VERSION 5.7 ;
BUSBITCHARS "[]" ;
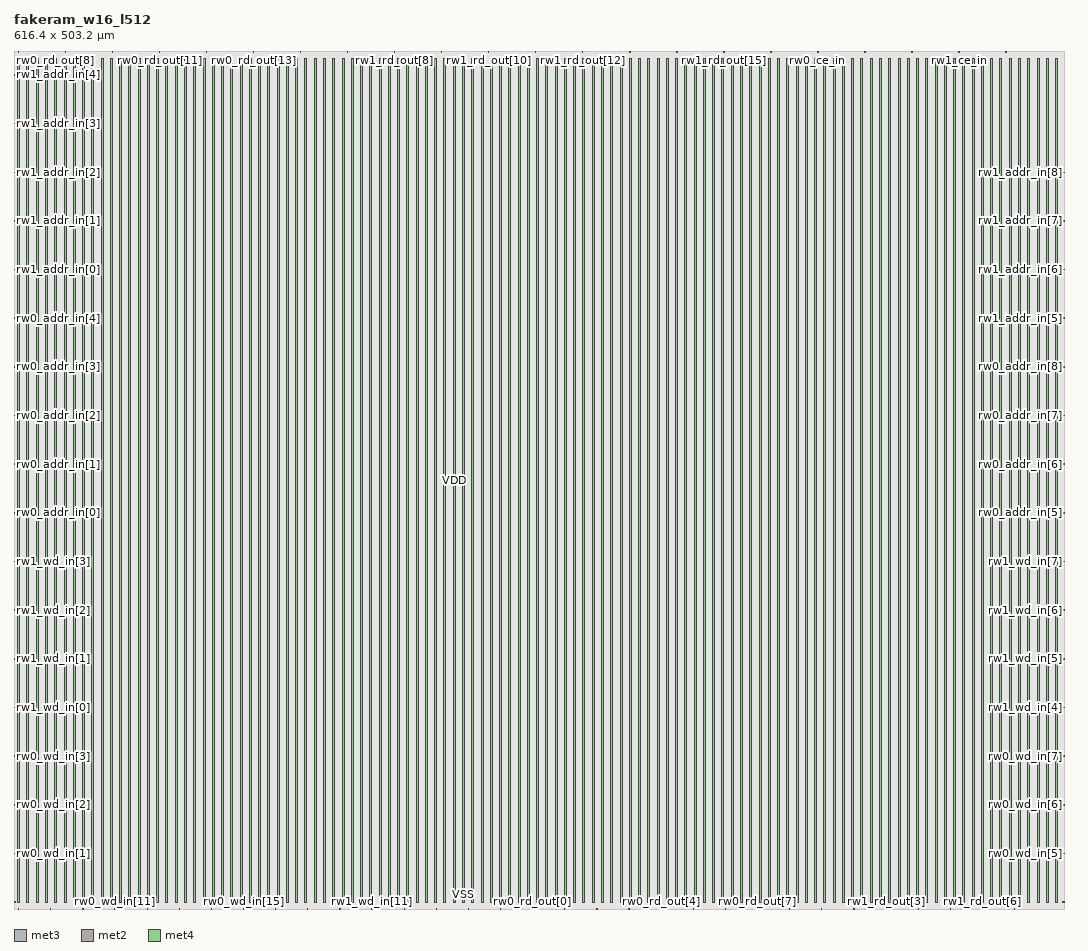
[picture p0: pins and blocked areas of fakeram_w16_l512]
MACRO fakeram_w16_l512
  FOREIGN fakeram_w16_l512 0 0 ;
  SYMMETRY X Y R90 ;
  SIZE 616.400 BY 503.200 ;
  CLASS BLOCK ;
  PIN rw0_wd_in[0]
    DIRECTION INPUT ;
    USE SIGNAL ;
    SHAPE ABUTMENT ;
    PORT
      LAYER met3 ;
      RECT 0.000 3.930 0.900 4.230 ;
    END
  END rw0_wd_in[0]
  PIN rw0_wd_in[1]
    DIRECTION INPUT ;
    USE SIGNAL ;
    SHAPE ABUTMENT ;
    PORT
      LAYER met3 ;
      RECT 0.000 32.490 0.900 32.790 ;
    END
  END rw0_wd_in[1]
  PIN rw0_wd_in[2]
    DIRECTION INPUT ;
    USE SIGNAL ;
    SHAPE ABUTMENT ;
    PORT
      LAYER met3 ;
      RECT 0.000 61.050 0.900 61.350 ;
    END
  END rw0_wd_in[2]
  PIN rw0_wd_in[3]
    DIRECTION INPUT ;
    USE SIGNAL ;
    SHAPE ABUTMENT ;
    PORT
      LAYER met3 ;
      RECT 0.000 89.610 0.900 89.910 ;
    END
  END rw0_wd_in[3]
  PIN rw0_wd_in[4]
    DIRECTION INPUT ;
    USE SIGNAL ;
    SHAPE ABUTMENT ;
    PORT
      LAYER met3 ;
      RECT 615.500 3.930 616.400 4.230 ;
    END
  END rw0_wd_in[4]
  PIN rw0_wd_in[5]
    DIRECTION INPUT ;
    USE SIGNAL ;
    SHAPE ABUTMENT ;
    PORT
      LAYER met3 ;
      RECT 615.500 32.490 616.400 32.790 ;
    END
  END rw0_wd_in[5]
  PIN rw0_wd_in[6]
    DIRECTION INPUT ;
    USE SIGNAL ;
    SHAPE ABUTMENT ;
    PORT
      LAYER met3 ;
      RECT 615.500 61.050 616.400 61.350 ;
    END
  END rw0_wd_in[6]
  PIN rw0_wd_in[7]
    DIRECTION INPUT ;
    USE SIGNAL ;
    SHAPE ABUTMENT ;
    PORT
      LAYER met3 ;
      RECT 615.500 89.610 616.400 89.910 ;
    END
  END rw0_wd_in[7]
  PIN rw0_wd_in[8]
    DIRECTION INPUT ;
    USE SIGNAL ;
    SHAPE ABUTMENT ;
    PORT
      LAYER met2 ;
      RECT 2.690 0.000 2.830 0.420 ;
    END
  END rw0_wd_in[8]
  PIN rw0_wd_in[9]
    DIRECTION INPUT ;
    USE SIGNAL ;
    SHAPE ABUTMENT ;
    PORT
      LAYER met2 ;
      RECT 21.550 0.000 21.690 0.420 ;
    END
  END rw0_wd_in[9]
  PIN rw0_wd_in[10]
    DIRECTION INPUT ;
    USE SIGNAL ;
    SHAPE ABUTMENT ;
    PORT
      LAYER met2 ;
      RECT 40.410 0.000 40.550 0.420 ;
    END
  END rw0_wd_in[10]
  PIN rw0_wd_in[11]
    DIRECTION INPUT ;
    USE SIGNAL ;
    SHAPE ABUTMENT ;
    PORT
      LAYER met2 ;
      RECT 59.270 0.000 59.410 0.420 ;
    END
  END rw0_wd_in[11]
  PIN rw0_wd_in[12]
    DIRECTION INPUT ;
    USE SIGNAL ;
    SHAPE ABUTMENT ;
    PORT
      LAYER met2 ;
      RECT 78.130 0.000 78.270 0.420 ;
    END
  END rw0_wd_in[12]
  PIN rw0_wd_in[13]
    DIRECTION INPUT ;
    USE SIGNAL ;
    SHAPE ABUTMENT ;
    PORT
      LAYER met2 ;
      RECT 96.990 0.000 97.130 0.420 ;
    END
  END rw0_wd_in[13]
  PIN rw0_wd_in[14]
    DIRECTION INPUT ;
    USE SIGNAL ;
    SHAPE ABUTMENT ;
    PORT
      LAYER met2 ;
      RECT 115.850 0.000 115.990 0.420 ;
    END
  END rw0_wd_in[14]
  PIN rw0_wd_in[15]
    DIRECTION INPUT ;
    USE SIGNAL ;
    SHAPE ABUTMENT ;
    PORT
      LAYER met2 ;
      RECT 134.710 0.000 134.850 0.420 ;
    END
  END rw0_wd_in[15]
  PIN rw1_wd_in[0]
    DIRECTION INPUT ;
    USE SIGNAL ;
    SHAPE ABUTMENT ;
    PORT
      LAYER met3 ;
      RECT 0.000 118.170 0.900 118.470 ;
    END
  END rw1_wd_in[0]
  PIN rw1_wd_in[1]
    DIRECTION INPUT ;
    USE SIGNAL ;
    SHAPE ABUTMENT ;
    PORT
      LAYER met3 ;
      RECT 0.000 146.730 0.900 147.030 ;
    END
  END rw1_wd_in[1]
  PIN rw1_wd_in[2]
    DIRECTION INPUT ;
    USE SIGNAL ;
    SHAPE ABUTMENT ;
    PORT
      LAYER met3 ;
      RECT 0.000 175.290 0.900 175.590 ;
    END
  END rw1_wd_in[2]
  PIN rw1_wd_in[3]
    DIRECTION INPUT ;
    USE SIGNAL ;
    SHAPE ABUTMENT ;
    PORT
      LAYER met3 ;
      RECT 0.000 203.850 0.900 204.150 ;
    END
  END rw1_wd_in[3]
  PIN rw1_wd_in[4]
    DIRECTION INPUT ;
    USE SIGNAL ;
    SHAPE ABUTMENT ;
    PORT
      LAYER met3 ;
      RECT 615.500 118.170 616.400 118.470 ;
    END
  END rw1_wd_in[4]
  PIN rw1_wd_in[5]
    DIRECTION INPUT ;
    USE SIGNAL ;
    SHAPE ABUTMENT ;
    PORT
      LAYER met3 ;
      RECT 615.500 146.730 616.400 147.030 ;
    END
  END rw1_wd_in[5]
  PIN rw1_wd_in[6]
    DIRECTION INPUT ;
    USE SIGNAL ;
    SHAPE ABUTMENT ;
    PORT
      LAYER met3 ;
      RECT 615.500 175.290 616.400 175.590 ;
    END
  END rw1_wd_in[6]
  PIN rw1_wd_in[7]
    DIRECTION INPUT ;
    USE SIGNAL ;
    SHAPE ABUTMENT ;
    PORT
      LAYER met3 ;
      RECT 615.500 203.850 616.400 204.150 ;
    END
  END rw1_wd_in[7]
  PIN rw1_wd_in[8]
    DIRECTION INPUT ;
    USE SIGNAL ;
    SHAPE ABUTMENT ;
    PORT
      LAYER met2 ;
      RECT 153.570 0.000 153.710 0.420 ;
    END
  END rw1_wd_in[8]
  PIN rw1_wd_in[9]
    DIRECTION INPUT ;
    USE SIGNAL ;
    SHAPE ABUTMENT ;
    PORT
      LAYER met2 ;
      RECT 172.430 0.000 172.570 0.420 ;
    END
  END rw1_wd_in[9]
  PIN rw1_wd_in[10]
    DIRECTION INPUT ;
    USE SIGNAL ;
    SHAPE ABUTMENT ;
    PORT
      LAYER met2 ;
      RECT 191.290 0.000 191.430 0.420 ;
    END
  END rw1_wd_in[10]
  PIN rw1_wd_in[11]
    DIRECTION INPUT ;
    USE SIGNAL ;
    SHAPE ABUTMENT ;
    PORT
      LAYER met2 ;
      RECT 210.150 0.000 210.290 0.420 ;
    END
  END rw1_wd_in[11]
  PIN rw1_wd_in[12]
    DIRECTION INPUT ;
    USE SIGNAL ;
    SHAPE ABUTMENT ;
    PORT
      LAYER met2 ;
      RECT 229.010 0.000 229.150 0.420 ;
    END
  END rw1_wd_in[12]
  PIN rw1_wd_in[13]
    DIRECTION INPUT ;
    USE SIGNAL ;
    SHAPE ABUTMENT ;
    PORT
      LAYER met2 ;
      RECT 247.870 0.000 248.010 0.420 ;
    END
  END rw1_wd_in[13]
  PIN rw1_wd_in[14]
    DIRECTION INPUT ;
    USE SIGNAL ;
    SHAPE ABUTMENT ;
    PORT
      LAYER met2 ;
      RECT 266.730 0.000 266.870 0.420 ;
    END
  END rw1_wd_in[14]
  PIN rw1_wd_in[15]
    DIRECTION INPUT ;
    USE SIGNAL ;
    SHAPE ABUTMENT ;
    PORT
      LAYER met2 ;
      RECT 285.590 0.000 285.730 0.420 ;
    END
  END rw1_wd_in[15]
  PIN rw0_rd_out[0]
    DIRECTION OUTPUT ;
    USE SIGNAL ;
    SHAPE ABUTMENT ;
    PORT
      LAYER met2 ;
      RECT 304.450 0.000 304.590 0.420 ;
    END
  END rw0_rd_out[0]
  PIN rw0_rd_out[1]
    DIRECTION OUTPUT ;
    USE SIGNAL ;
    SHAPE ABUTMENT ;
    PORT
      LAYER met2 ;
      RECT 323.310 0.000 323.450 0.420 ;
    END
  END rw0_rd_out[1]
  PIN rw0_rd_out[2]
    DIRECTION OUTPUT ;
    USE SIGNAL ;
    SHAPE ABUTMENT ;
    PORT
      LAYER met2 ;
      RECT 342.170 0.000 342.310 0.420 ;
    END
  END rw0_rd_out[2]
  PIN rw0_rd_out[3]
    DIRECTION OUTPUT ;
    USE SIGNAL ;
    SHAPE ABUTMENT ;
    PORT
      LAYER met2 ;
      RECT 361.030 0.000 361.170 0.420 ;
    END
  END rw0_rd_out[3]
  PIN rw0_rd_out[4]
    DIRECTION OUTPUT ;
    USE SIGNAL ;
    SHAPE ABUTMENT ;
    PORT
      LAYER met2 ;
      RECT 379.890 0.000 380.030 0.420 ;
    END
  END rw0_rd_out[4]
  PIN rw0_rd_out[5]
    DIRECTION OUTPUT ;
    USE SIGNAL ;
    SHAPE ABUTMENT ;
    PORT
      LAYER met2 ;
      RECT 398.750 0.000 398.890 0.420 ;
    END
  END rw0_rd_out[5]
  PIN rw0_rd_out[6]
    DIRECTION OUTPUT ;
    USE SIGNAL ;
    SHAPE ABUTMENT ;
    PORT
      LAYER met2 ;
      RECT 417.610 0.000 417.750 0.420 ;
    END
  END rw0_rd_out[6]
  PIN rw0_rd_out[7]
    DIRECTION OUTPUT ;
    USE SIGNAL ;
    SHAPE ABUTMENT ;
    PORT
      LAYER met2 ;
      RECT 436.470 0.000 436.610 0.420 ;
    END
  END rw0_rd_out[7]
  PIN rw0_rd_out[8]
    DIRECTION OUTPUT ;
    USE SIGNAL ;
    SHAPE ABUTMENT ;
    PORT
      LAYER met2 ;
      RECT 2.690 502.780 2.830 503.200 ;
    END
  END rw0_rd_out[8]
  PIN rw0_rd_out[9]
    DIRECTION OUTPUT ;
    USE SIGNAL ;
    SHAPE ABUTMENT ;
    PORT
      LAYER met2 ;
      RECT 30.290 502.780 30.430 503.200 ;
    END
  END rw0_rd_out[9]
  PIN rw0_rd_out[10]
    DIRECTION OUTPUT ;
    USE SIGNAL ;
    SHAPE ABUTMENT ;
    PORT
      LAYER met2 ;
      RECT 57.890 502.780 58.030 503.200 ;
    END
  END rw0_rd_out[10]
  PIN rw0_rd_out[11]
    DIRECTION OUTPUT ;
    USE SIGNAL ;
    SHAPE ABUTMENT ;
    PORT
      LAYER met2 ;
      RECT 85.490 502.780 85.630 503.200 ;
    END
  END rw0_rd_out[11]
  PIN rw0_rd_out[12]
    DIRECTION OUTPUT ;
    USE SIGNAL ;
    SHAPE ABUTMENT ;
    PORT
      LAYER met2 ;
      RECT 113.090 502.780 113.230 503.200 ;
    END
  END rw0_rd_out[12]
  PIN rw0_rd_out[13]
    DIRECTION OUTPUT ;
    USE SIGNAL ;
    SHAPE ABUTMENT ;
    PORT
      LAYER met2 ;
      RECT 140.690 502.780 140.830 503.200 ;
    END
  END rw0_rd_out[13]
  PIN rw0_rd_out[14]
    DIRECTION OUTPUT ;
    USE SIGNAL ;
    SHAPE ABUTMENT ;
    PORT
      LAYER met2 ;
      RECT 168.290 502.780 168.430 503.200 ;
    END
  END rw0_rd_out[14]
  PIN rw0_rd_out[15]
    DIRECTION OUTPUT ;
    USE SIGNAL ;
    SHAPE ABUTMENT ;
    PORT
      LAYER met2 ;
      RECT 195.890 502.780 196.030 503.200 ;
    END
  END rw0_rd_out[15]
  PIN rw1_rd_out[0]
    DIRECTION OUTPUT ;
    USE SIGNAL ;
    SHAPE ABUTMENT ;
    PORT
      LAYER met2 ;
      RECT 455.330 0.000 455.470 0.420 ;
    END
  END rw1_rd_out[0]
  PIN rw1_rd_out[1]
    DIRECTION OUTPUT ;
    USE SIGNAL ;
    SHAPE ABUTMENT ;
    PORT
      LAYER met2 ;
      RECT 474.190 0.000 474.330 0.420 ;
    END
  END rw1_rd_out[1]
  PIN rw1_rd_out[2]
    DIRECTION OUTPUT ;
    USE SIGNAL ;
    SHAPE ABUTMENT ;
    PORT
      LAYER met2 ;
      RECT 493.050 0.000 493.190 0.420 ;
    END
  END rw1_rd_out[2]
  PIN rw1_rd_out[3]
    DIRECTION OUTPUT ;
    USE SIGNAL ;
    SHAPE ABUTMENT ;
    PORT
      LAYER met2 ;
      RECT 511.910 0.000 512.050 0.420 ;
    END
  END rw1_rd_out[3]
  PIN rw1_rd_out[4]
    DIRECTION OUTPUT ;
    USE SIGNAL ;
    SHAPE ABUTMENT ;
    PORT
      LAYER met2 ;
      RECT 530.770 0.000 530.910 0.420 ;
    END
  END rw1_rd_out[4]
  PIN rw1_rd_out[5]
    DIRECTION OUTPUT ;
    USE SIGNAL ;
    SHAPE ABUTMENT ;
    PORT
      LAYER met2 ;
      RECT 549.630 0.000 549.770 0.420 ;
    END
  END rw1_rd_out[5]
  PIN rw1_rd_out[6]
    DIRECTION OUTPUT ;
    USE SIGNAL ;
    SHAPE ABUTMENT ;
    PORT
      LAYER met2 ;
      RECT 568.490 0.000 568.630 0.420 ;
    END
  END rw1_rd_out[6]
  PIN rw1_rd_out[7]
    DIRECTION OUTPUT ;
    USE SIGNAL ;
    SHAPE ABUTMENT ;
    PORT
      LAYER met2 ;
      RECT 587.350 0.000 587.490 0.420 ;
    END
  END rw1_rd_out[7]
  PIN rw1_rd_out[8]
    DIRECTION OUTPUT ;
    USE SIGNAL ;
    SHAPE ABUTMENT ;
    PORT
      LAYER met2 ;
      RECT 223.490 502.780 223.630 503.200 ;
    END
  END rw1_rd_out[8]
  PIN rw1_rd_out[9]
    DIRECTION OUTPUT ;
    USE SIGNAL ;
    SHAPE ABUTMENT ;
    PORT
      LAYER met2 ;
      RECT 251.090 502.780 251.230 503.200 ;
    END
  END rw1_rd_out[9]
  PIN rw1_rd_out[10]
    DIRECTION OUTPUT ;
    USE SIGNAL ;
    SHAPE ABUTMENT ;
    PORT
      LAYER met2 ;
      RECT 278.690 502.780 278.830 503.200 ;
    END
  END rw1_rd_out[10]
  PIN rw1_rd_out[11]
    DIRECTION OUTPUT ;
    USE SIGNAL ;
    SHAPE ABUTMENT ;
    PORT
      LAYER met2 ;
      RECT 306.290 502.780 306.430 503.200 ;
    END
  END rw1_rd_out[11]
  PIN rw1_rd_out[12]
    DIRECTION OUTPUT ;
    USE SIGNAL ;
    SHAPE ABUTMENT ;
    PORT
      LAYER met2 ;
      RECT 333.890 502.780 334.030 503.200 ;
    END
  END rw1_rd_out[12]
  PIN rw1_rd_out[13]
    DIRECTION OUTPUT ;
    USE SIGNAL ;
    SHAPE ABUTMENT ;
    PORT
      LAYER met2 ;
      RECT 361.490 502.780 361.630 503.200 ;
    END
  END rw1_rd_out[13]
  PIN rw1_rd_out[14]
    DIRECTION OUTPUT ;
    USE SIGNAL ;
    SHAPE ABUTMENT ;
    PORT
      LAYER met2 ;
      RECT 389.090 502.780 389.230 503.200 ;
    END
  END rw1_rd_out[14]
  PIN rw1_rd_out[15]
    DIRECTION OUTPUT ;
    USE SIGNAL ;
    SHAPE ABUTMENT ;
    PORT
      LAYER met2 ;
      RECT 416.690 502.780 416.830 503.200 ;
    END
  END rw1_rd_out[15]
  PIN rw0_addr_in[0]
    DIRECTION INPUT ;
    USE SIGNAL ;
    SHAPE ABUTMENT ;
    PORT
      LAYER met3 ;
      RECT 0.000 232.410 0.900 232.710 ;
    END
  END rw0_addr_in[0]
  PIN rw0_addr_in[1]
    DIRECTION INPUT ;
    USE SIGNAL ;
    SHAPE ABUTMENT ;
    PORT
      LAYER met3 ;
      RECT 0.000 260.970 0.900 261.270 ;
    END
  END rw0_addr_in[1]
  PIN rw0_addr_in[2]
    DIRECTION INPUT ;
    USE SIGNAL ;
    SHAPE ABUTMENT ;
    PORT
      LAYER met3 ;
      RECT 0.000 289.530 0.900 289.830 ;
    END
  END rw0_addr_in[2]
  PIN rw0_addr_in[3]
    DIRECTION INPUT ;
    USE SIGNAL ;
    SHAPE ABUTMENT ;
    PORT
      LAYER met3 ;
      RECT 0.000 318.090 0.900 318.390 ;
    END
  END rw0_addr_in[3]
  PIN rw0_addr_in[4]
    DIRECTION INPUT ;
    USE SIGNAL ;
    SHAPE ABUTMENT ;
    PORT
      LAYER met3 ;
      RECT 0.000 346.650 0.900 346.950 ;
    END
  END rw0_addr_in[4]
  PIN rw0_addr_in[5]
    DIRECTION INPUT ;
    USE SIGNAL ;
    SHAPE ABUTMENT ;
    PORT
      LAYER met3 ;
      RECT 615.500 232.410 616.400 232.710 ;
    END
  END rw0_addr_in[5]
  PIN rw0_addr_in[6]
    DIRECTION INPUT ;
    USE SIGNAL ;
    SHAPE ABUTMENT ;
    PORT
      LAYER met3 ;
      RECT 615.500 260.970 616.400 261.270 ;
    END
  END rw0_addr_in[6]
  PIN rw0_addr_in[7]
    DIRECTION INPUT ;
    USE SIGNAL ;
    SHAPE ABUTMENT ;
    PORT
      LAYER met3 ;
      RECT 615.500 289.530 616.400 289.830 ;
    END
  END rw0_addr_in[7]
  PIN rw0_addr_in[8]
    DIRECTION INPUT ;
    USE SIGNAL ;
    SHAPE ABUTMENT ;
    PORT
      LAYER met3 ;
      RECT 615.500 318.090 616.400 318.390 ;
    END
  END rw0_addr_in[8]
  PIN rw1_addr_in[0]
    DIRECTION INPUT ;
    USE SIGNAL ;
    SHAPE ABUTMENT ;
    PORT
      LAYER met3 ;
      RECT 0.000 375.210 0.900 375.510 ;
    END
  END rw1_addr_in[0]
  PIN rw1_addr_in[1]
    DIRECTION INPUT ;
    USE SIGNAL ;
    SHAPE ABUTMENT ;
    PORT
      LAYER met3 ;
      RECT 0.000 403.770 0.900 404.070 ;
    END
  END rw1_addr_in[1]
  PIN rw1_addr_in[2]
    DIRECTION INPUT ;
    USE SIGNAL ;
    SHAPE ABUTMENT ;
    PORT
      LAYER met3 ;
      RECT 0.000 432.330 0.900 432.630 ;
    END
  END rw1_addr_in[2]
  PIN rw1_addr_in[3]
    DIRECTION INPUT ;
    USE SIGNAL ;
    SHAPE ABUTMENT ;
    PORT
      LAYER met3 ;
      RECT 0.000 460.890 0.900 461.190 ;
    END
  END rw1_addr_in[3]
  PIN rw1_addr_in[4]
    DIRECTION INPUT ;
    USE SIGNAL ;
    SHAPE ABUTMENT ;
    PORT
      LAYER met3 ;
      RECT 0.000 489.450 0.900 489.750 ;
    END
  END rw1_addr_in[4]
  PIN rw1_addr_in[5]
    DIRECTION INPUT ;
    USE SIGNAL ;
    SHAPE ABUTMENT ;
    PORT
      LAYER met3 ;
      RECT 615.500 346.650 616.400 346.950 ;
    END
  END rw1_addr_in[5]
  PIN rw1_addr_in[6]
    DIRECTION INPUT ;
    USE SIGNAL ;
    SHAPE ABUTMENT ;
    PORT
      LAYER met3 ;
      RECT 615.500 375.210 616.400 375.510 ;
    END
  END rw1_addr_in[6]
  PIN rw1_addr_in[7]
    DIRECTION INPUT ;
    USE SIGNAL ;
    SHAPE ABUTMENT ;
    PORT
      LAYER met3 ;
      RECT 615.500 403.770 616.400 404.070 ;
    END
  END rw1_addr_in[7]
  PIN rw1_addr_in[8]
    DIRECTION INPUT ;
    USE SIGNAL ;
    SHAPE ABUTMENT ;
    PORT
      LAYER met3 ;
      RECT 615.500 432.330 616.400 432.630 ;
    END
  END rw1_addr_in[8]
  PIN rw0_we_in
    DIRECTION INPUT ;
    USE SIGNAL ;
    SHAPE ABUTMENT ;
    PORT
      LAYER met2 ;
      RECT 444.290 502.780 444.430 503.200 ;
    END
  END rw0_we_in
  PIN rw0_ce_in
    DIRECTION INPUT ;
    USE SIGNAL ;
    SHAPE ABUTMENT ;
    PORT
      LAYER met2 ;
      RECT 471.890 502.780 472.030 503.200 ;
    END
  END rw0_ce_in
  PIN rw0_clk
    DIRECTION INPUT ;
    USE SIGNAL ;
    SHAPE ABUTMENT ;
    PORT
      LAYER met2 ;
      RECT 499.490 502.780 499.630 503.200 ;
    END
  END rw0_clk
  PIN rw1_we_in
    DIRECTION INPUT ;
    USE SIGNAL ;
    SHAPE ABUTMENT ;
    PORT
      LAYER met2 ;
      RECT 527.090 502.780 527.230 503.200 ;
    END
  END rw1_we_in
  PIN rw1_ce_in
    DIRECTION INPUT ;
    USE SIGNAL ;
    SHAPE ABUTMENT ;
    PORT
      LAYER met2 ;
      RECT 554.690 502.780 554.830 503.200 ;
    END
  END rw1_ce_in
  PIN rw1_clk
    DIRECTION INPUT ;
    USE SIGNAL ;
    SHAPE ABUTMENT ;
    PORT
      LAYER met2 ;
      RECT 582.290 502.780 582.430 503.200 ;
    END
  END rw1_clk
  PIN VSS
    DIRECTION INOUT ;
    USE GROUND ;
    PORT
      LAYER met4 ;
      RECT 2.160 4.080 3.360 499.120 ;
      RECT 13.040 4.080 14.240 499.120 ;
      RECT 23.920 4.080 25.120 499.120 ;
      RECT 34.800 4.080 36.000 499.120 ;
      RECT 45.680 4.080 46.880 499.120 ;
      RECT 56.560 4.080 57.760 499.120 ;
      RECT 67.440 4.080 68.640 499.120 ;
      RECT 78.320 4.080 79.520 499.120 ;
      RECT 89.200 4.080 90.400 499.120 ;
      RECT 100.080 4.080 101.280 499.120 ;
      RECT 110.960 4.080 112.160 499.120 ;
      RECT 121.840 4.080 123.040 499.120 ;
      RECT 132.720 4.080 133.920 499.120 ;
      RECT 143.600 4.080 144.800 499.120 ;
      RECT 154.480 4.080 155.680 499.120 ;
      RECT 165.360 4.080 166.560 499.120 ;
      RECT 176.240 4.080 177.440 499.120 ;
      RECT 187.120 4.080 188.320 499.120 ;
      RECT 198.000 4.080 199.200 499.120 ;
      RECT 208.880 4.080 210.080 499.120 ;
      RECT 219.760 4.080 220.960 499.120 ;
      RECT 230.640 4.080 231.840 499.120 ;
      RECT 241.520 4.080 242.720 499.120 ;
      RECT 252.400 4.080 253.600 499.120 ;
      RECT 263.280 4.080 264.480 499.120 ;
      RECT 274.160 4.080 275.360 499.120 ;
      RECT 285.040 4.080 286.240 499.120 ;
      RECT 295.920 4.080 297.120 499.120 ;
      RECT 306.800 4.080 308.000 499.120 ;
      RECT 317.680 4.080 318.880 499.120 ;
      RECT 328.560 4.080 329.760 499.120 ;
      RECT 339.440 4.080 340.640 499.120 ;
      RECT 350.320 4.080 351.520 499.120 ;
      RECT 361.200 4.080 362.400 499.120 ;
      RECT 372.080 4.080 373.280 499.120 ;
      RECT 382.960 4.080 384.160 499.120 ;
      RECT 393.840 4.080 395.040 499.120 ;
      RECT 404.720 4.080 405.920 499.120 ;
      RECT 415.600 4.080 416.800 499.120 ;
      RECT 426.480 4.080 427.680 499.120 ;
      RECT 437.360 4.080 438.560 499.120 ;
      RECT 448.240 4.080 449.440 499.120 ;
      RECT 459.120 4.080 460.320 499.120 ;
      RECT 470.000 4.080 471.200 499.120 ;
      RECT 480.880 4.080 482.080 499.120 ;
      RECT 491.760 4.080 492.960 499.120 ;
      RECT 502.640 4.080 503.840 499.120 ;
      RECT 513.520 4.080 514.720 499.120 ;
      RECT 524.400 4.080 525.600 499.120 ;
      RECT 535.280 4.080 536.480 499.120 ;
      RECT 546.160 4.080 547.360 499.120 ;
      RECT 557.040 4.080 558.240 499.120 ;
      RECT 567.920 4.080 569.120 499.120 ;
      RECT 578.800 4.080 580.000 499.120 ;
      RECT 589.680 4.080 590.880 499.120 ;
      RECT 600.560 4.080 601.760 499.120 ;
      RECT 611.440 4.080 612.640 499.120 ;
    END
  END VSS
  PIN VDD
    DIRECTION INOUT ;
    USE POWER ;
    PORT
      LAYER met4 ;
      RECT 7.600 4.080 8.800 499.120 ;
      RECT 18.480 4.080 19.680 499.120 ;
      RECT 29.360 4.080 30.560 499.120 ;
      RECT 40.240 4.080 41.440 499.120 ;
      RECT 51.120 4.080 52.320 499.120 ;
      RECT 62.000 4.080 63.200 499.120 ;
      RECT 72.880 4.080 74.080 499.120 ;
      RECT 83.760 4.080 84.960 499.120 ;
      RECT 94.640 4.080 95.840 499.120 ;
      RECT 105.520 4.080 106.720 499.120 ;
      RECT 116.400 4.080 117.600 499.120 ;
      RECT 127.280 4.080 128.480 499.120 ;
      RECT 138.160 4.080 139.360 499.120 ;
      RECT 149.040 4.080 150.240 499.120 ;
      RECT 159.920 4.080 161.120 499.120 ;
      RECT 170.800 4.080 172.000 499.120 ;
      RECT 181.680 4.080 182.880 499.120 ;
      RECT 192.560 4.080 193.760 499.120 ;
      RECT 203.440 4.080 204.640 499.120 ;
      RECT 214.320 4.080 215.520 499.120 ;
      RECT 225.200 4.080 226.400 499.120 ;
      RECT 236.080 4.080 237.280 499.120 ;
      RECT 246.960 4.080 248.160 499.120 ;
      RECT 257.840 4.080 259.040 499.120 ;
      RECT 268.720 4.080 269.920 499.120 ;
      RECT 279.600 4.080 280.800 499.120 ;
      RECT 290.480 4.080 291.680 499.120 ;
      RECT 301.360 4.080 302.560 499.120 ;
      RECT 312.240 4.080 313.440 499.120 ;
      RECT 323.120 4.080 324.320 499.120 ;
      RECT 334.000 4.080 335.200 499.120 ;
      RECT 344.880 4.080 346.080 499.120 ;
      RECT 355.760 4.080 356.960 499.120 ;
      RECT 366.640 4.080 367.840 499.120 ;
      RECT 377.520 4.080 378.720 499.120 ;
      RECT 388.400 4.080 389.600 499.120 ;
      RECT 399.280 4.080 400.480 499.120 ;
      RECT 410.160 4.080 411.360 499.120 ;
      RECT 421.040 4.080 422.240 499.120 ;
      RECT 431.920 4.080 433.120 499.120 ;
      RECT 442.800 4.080 444.000 499.120 ;
      RECT 453.680 4.080 454.880 499.120 ;
      RECT 464.560 4.080 465.760 499.120 ;
      RECT 475.440 4.080 476.640 499.120 ;
      RECT 486.320 4.080 487.520 499.120 ;
      RECT 497.200 4.080 498.400 499.120 ;
      RECT 508.080 4.080 509.280 499.120 ;
      RECT 518.960 4.080 520.160 499.120 ;
      RECT 529.840 4.080 531.040 499.120 ;
      RECT 540.720 4.080 541.920 499.120 ;
      RECT 551.600 4.080 552.800 499.120 ;
      RECT 562.480 4.080 563.680 499.120 ;
      RECT 573.360 4.080 574.560 499.120 ;
      RECT 584.240 4.080 585.440 499.120 ;
      RECT 595.120 4.080 596.320 499.120 ;
      RECT 606.000 4.080 607.200 499.120 ;
    END
  END VDD
  OBS
    LAYER met1 ;
    RECT 0 0 616.400 503.200 ;
    LAYER met2 ;
    RECT 0 0 616.400 503.200 ;
    LAYER met3 ;
    RECT 0 0 616.400 503.200 ;
    LAYER met4 ;
    RECT 0 0 616.400 503.200 ;
  END
END fakeram_w16_l512

END LIBRARY
